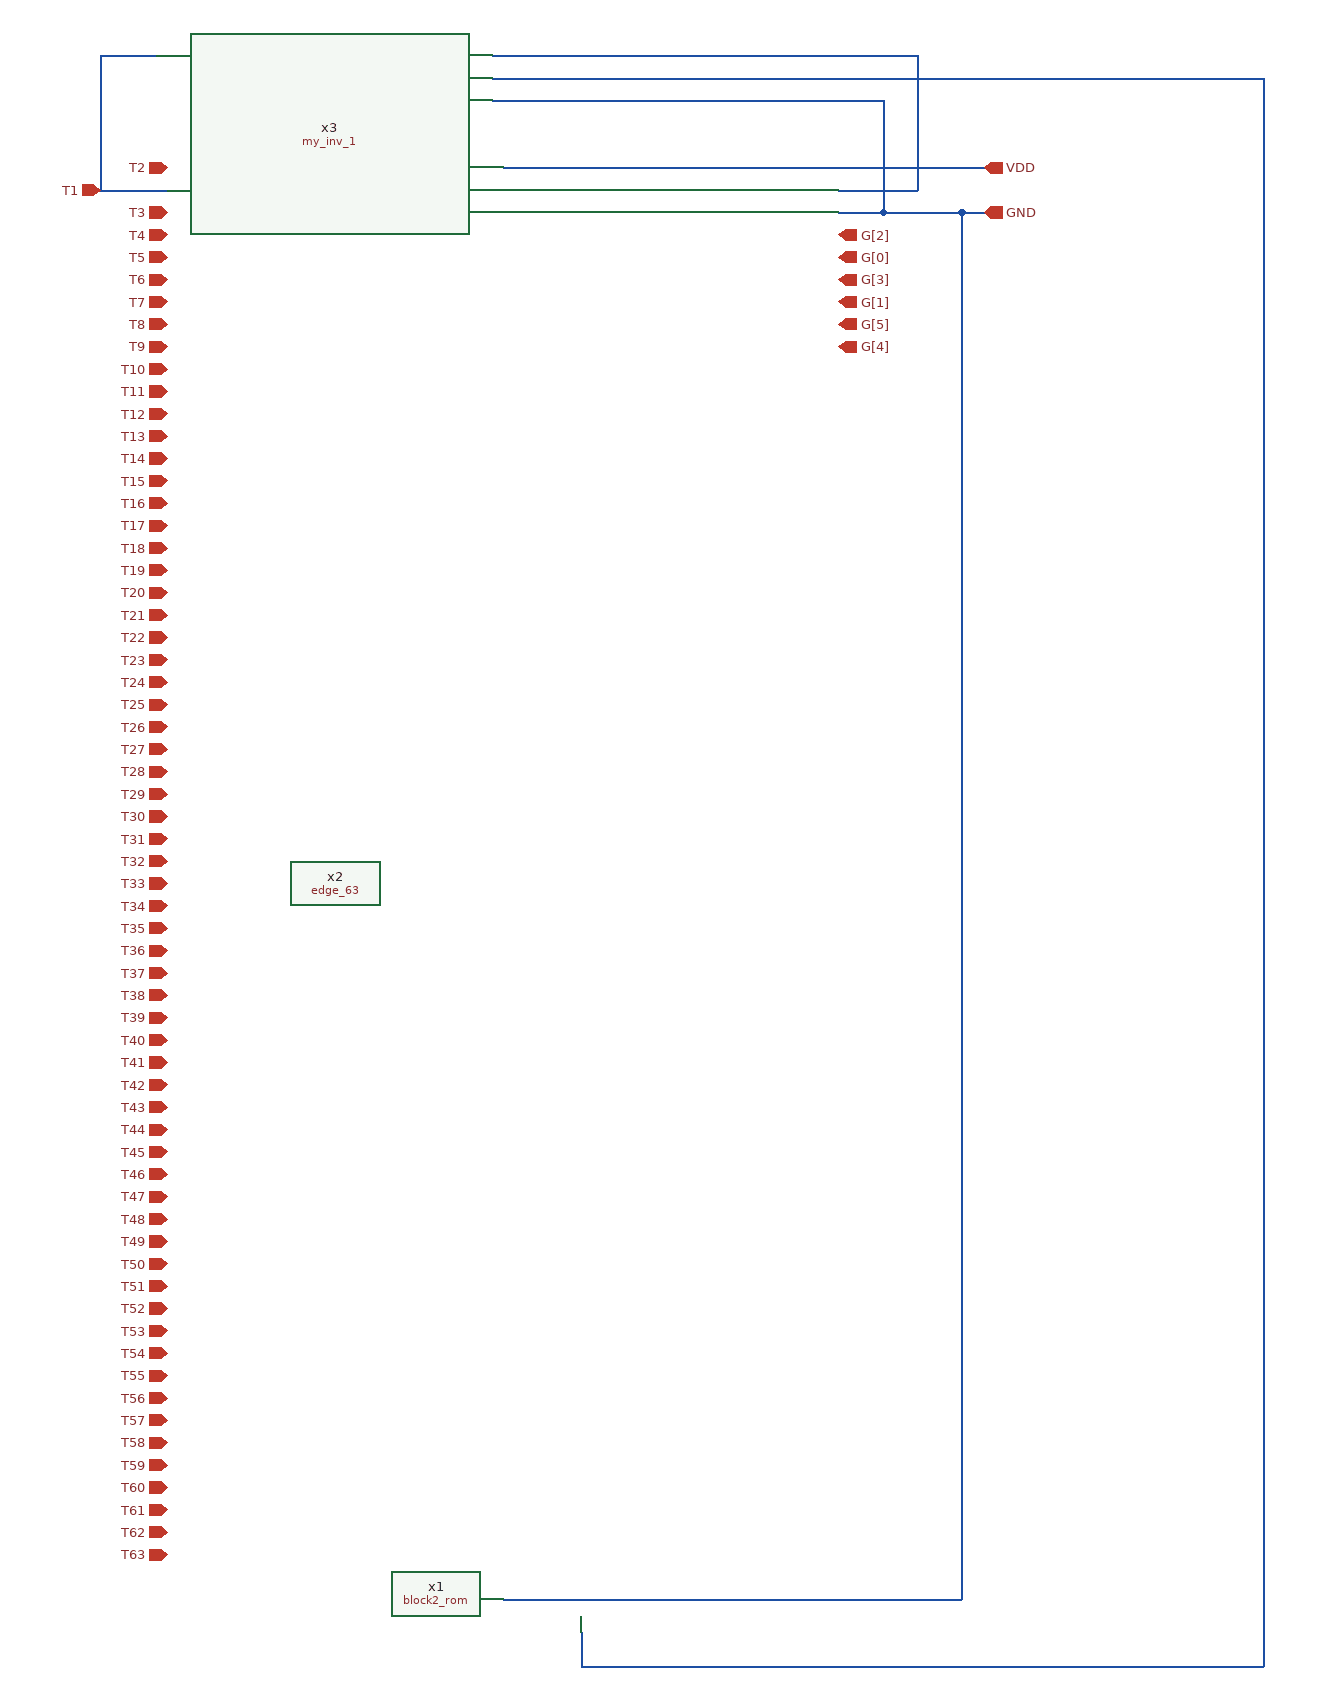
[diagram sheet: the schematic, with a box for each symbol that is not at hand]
v {xschem version=3.4.5 file_version=1.2
}
G {}
K {}
V {}
S {}
E {}
N -470 -860 -470 -740 {
lab=T1}
N -470 -860 -420 -860 {
lab=T1}
N -470 -740 -410 -740 {
lab=T1}
N -120 -820 230 -820 {
lab=GND}
N -120 -860 260 -860 {
lab=VDD}
N -120 -840 570 -840 {
lab=#net1}
N 570 -840 570 580 {
lab=#net1}
N -40 580 570 580 {
lab=#net1}
N -40 550 -40 580 {
lab=#net1}
N 260 -860 260 -740 {
lab=VDD}
N 190 -740 260 -740 {
lab=VDD}
N 230 -820 230 -720 {
lab=GND}
N 190 -720 230 -720 {
lab=GND}
N -110 -760 260 -760 {
lab=VDD}
N -110 520 300 520 {
lab=GND}
N 300 -720 300 520 {
lab=GND}
N 230 -720 300 -720 {
lab=GND}
N 300 -720 320 -720 {
lab=GND}
N 260 -760 320 -760 {
lab=VDD}
C {devices/ipin.sym} -410 -760 0 0 {name=p1 lab=T2}
C {devices/ipin.sym} -470 -740 0 0 {name=p2 lab=T1}
C {devices/ipin.sym} -410 -720 0 0 {name=p3 lab=T3}
C {devices/ipin.sym} -410 -700 0 0 {name=p4 lab=T4}
C {devices/ipin.sym} -410 -680 0 0 {name=p5 lab=T5}
C {devices/ipin.sym} -410 -660 0 0 {name=p6 lab=T6}
C {devices/ipin.sym} -410 -640 0 0 {name=p7 lab=T7
}
C {devices/ipin.sym} -410 -620 0 0 {name=p8 lab=T8}
C {devices/ipin.sym} -410 -600 0 0 {name=p9 lab=T9}
C {devices/ipin.sym} -410 -580 0 0 {name=p10 lab=T10}
C {devices/ipin.sym} -410 -560 0 0 {name=p11 lab=T11}
C {devices/ipin.sym} -410 -540 0 0 {name=p12 lab=T12}
C {devices/ipin.sym} -410 -520 0 0 {name=p13 lab=T13}
C {devices/ipin.sym} -410 -500 0 0 {name=p14 lab=T14}
C {devices/ipin.sym} -410 -480 0 0 {name=p15 lab=T15}
C {devices/ipin.sym} -410 -460 0 0 {name=p16 lab=T16}
C {devices/ipin.sym} -410 -440 0 0 {name=p17 lab=T17
}
C {devices/ipin.sym} -410 -420 0 0 {name=p18 lab=T18}
C {devices/ipin.sym} -410 -400 0 0 {name=p19 lab=T19}
C {devices/ipin.sym} -410 -380 0 0 {name=p20 lab=T20}
C {devices/ipin.sym} -410 -360 0 0 {name=p21 lab=T21}
C {devices/ipin.sym} -410 -340 0 0 {name=p22 lab=T22}
C {devices/ipin.sym} -410 -320 0 0 {name=p23 lab=T23}
C {devices/ipin.sym} -410 -300 0 0 {name=p24 lab=T24}
C {devices/ipin.sym} -410 -280 0 0 {name=p25 lab=T25}
C {devices/ipin.sym} -410 -260 0 0 {name=p26 lab=T26}
C {devices/ipin.sym} -410 -240 0 0 {name=p27 lab=T27}
C {devices/ipin.sym} -410 -220 0 0 {name=p28 lab=T28}
C {devices/ipin.sym} -410 -200 0 0 {name=p29 lab=T29}
C {devices/ipin.sym} -410 -180 0 0 {name=p30 lab=T30}
C {devices/ipin.sym} -410 -160 0 0 {name=p31 lab=T31}
C {devices/ipin.sym} -410 -140 0 0 {name=p32 lab=T32}
C {devices/ipin.sym} -410 -120 0 0 {name=p33 lab=T33}
C {devices/ipin.sym} -410 -100 0 0 {name=p34 lab=T34}
C {devices/ipin.sym} -410 -80 0 0 {name=p35 lab=T35}
C {devices/ipin.sym} -410 -60 0 0 {name=p36 lab=T36}
C {devices/ipin.sym} -410 -40 0 0 {name=p37 lab=T37
}
C {devices/ipin.sym} -410 -20 0 0 {name=p38 lab=T38}
C {devices/ipin.sym} -410 0 0 0 {name=p39 lab=T39}
C {devices/ipin.sym} -410 20 0 0 {name=p40 lab=T40}
C {devices/ipin.sym} -410 40 0 0 {name=p41 lab=T41}
C {devices/ipin.sym} -410 60 0 0 {name=p42 lab=T42}
C {devices/ipin.sym} -410 80 0 0 {name=p43 lab=T43}
C {devices/ipin.sym} -410 100 0 0 {name=p44 lab=T44}
C {devices/ipin.sym} -410 120 0 0 {name=p45 lab=T45}
C {devices/ipin.sym} -410 140 0 0 {name=p46 lab=T46}
C {devices/ipin.sym} -410 160 0 0 {name=p47 lab=T47
}
C {devices/ipin.sym} -410 180 0 0 {name=p48 lab=T48}
C {devices/ipin.sym} -410 200 0 0 {name=p49 lab=T49}
C {devices/ipin.sym} -410 220 0 0 {name=p50 lab=T50}
C {devices/ipin.sym} -410 240 0 0 {name=p51 lab=T51}
C {devices/ipin.sym} -410 260 0 0 {name=p52 lab=T52}
C {devices/ipin.sym} -410 280 0 0 {name=p53 lab=T53}
C {devices/ipin.sym} -410 300 0 0 {name=p54 lab=T54}
C {devices/ipin.sym} -410 320 0 0 {name=p55 lab=T55}
C {devices/ipin.sym} -410 340 0 0 {name=p56 lab=T56}
C {devices/ipin.sym} -410 360 0 0 {name=p57 lab=T57}
C {devices/ipin.sym} -410 380 0 0 {name=p58 lab=T58
}
C {devices/ipin.sym} -410 400 0 0 {name=p59 lab=T59}
C {devices/ipin.sym} -410 420 0 0 {name=p60 lab=T60}
C {devices/ipin.sym} -410 440 0 0 {name=p61 lab=T61}
C {devices/ipin.sym} -410 460 0 0 {name=p62 lab=T62}
C {devices/ipin.sym} -410 480 0 0 {name=p63 lab=T63}
C {devices/opin.sym} 190 -700 0 0 {name=p64 lab=G[2]}
C {devices/opin.sym} 190 -680 0 0 {name=p65 lab=G[0]}
C {devices/opin.sym} 190 -660 0 0 {name=p66 lab=G[3]}
C {devices/opin.sym} 190 -640 0 0 {name=p67 lab=G[1]}
C {devices/opin.sym} 190 -620 0 0 {name=p68 lab=G[5]}
C {devices/opin.sym} 190 -600 0 0 {name=p69 lab=G[4]}
C {/home/huydq/Downloads/Pseudo-NMOS-ROM-Encoder-master/my_inv_1.sym} -270 -840 0 0 {name=x3}
C {/home/huydq/Downloads/Pseudo-NMOS-ROM-Encoder-master/block2_rom.sym} 40 -110 0 0 {name=x1}
C {devices/ipin.sym} 320 -760 0 1 {name=p70 lab=VDD}
C {devices/ipin.sym} 320 -720 0 1 {name=p71 lab=GND}
C {/home/huydq/Downloads/Pseudo-NMOS-ROM-Encoder-master/edge_63.sym} -260 -120 0 0 {name=x2}
